VERSION 5.8 ;
BUSBITCHARS "[]" ;
DIVIDERCHAR "/" ;
UNITS
    DATABASE MICRONS 2000 ;
END UNITS

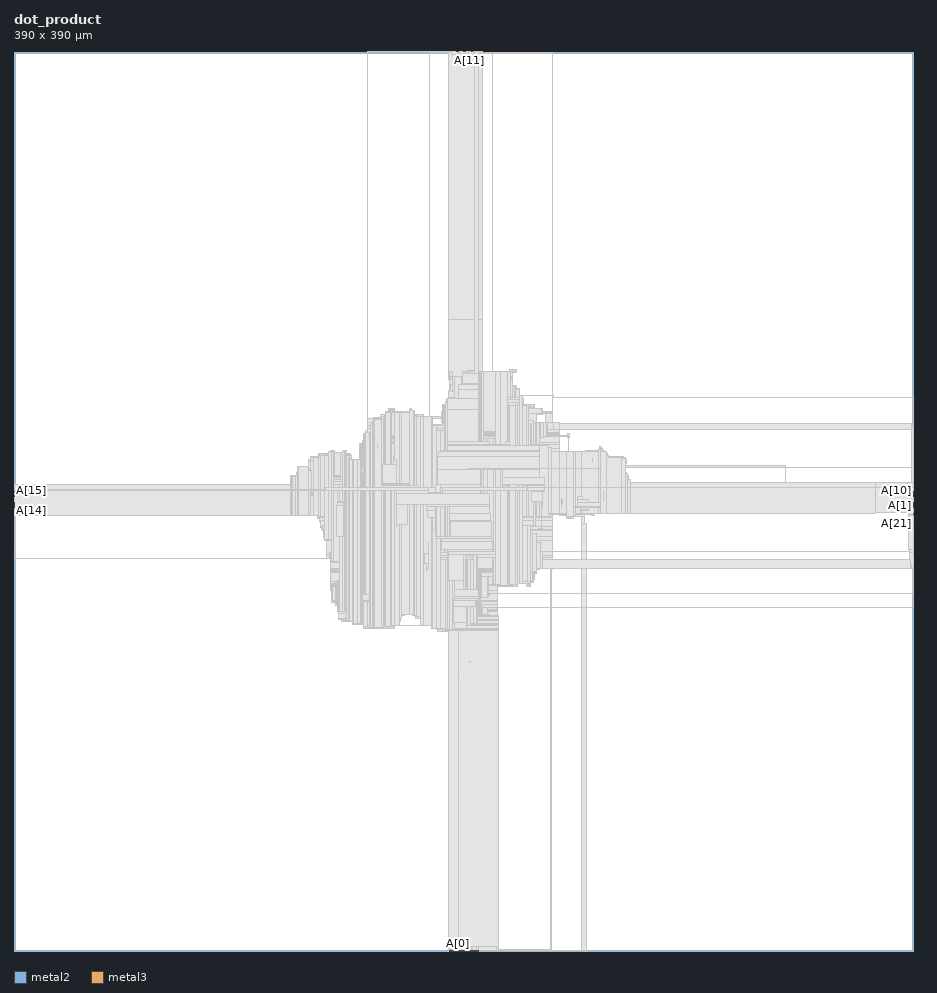
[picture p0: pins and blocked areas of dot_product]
MACRO dot_product
  FOREIGN dot_product 0 0 ;
  CLASS BLOCK ;
  SIZE 390 BY 390 ;
  PIN A[0]
    DIRECTION INPUT ;
    USE SIGNAL ;
    PORT
      LAYER metal2 ;
        RECT  192.34 0 192.41 0.07 ;
    END
  END A[0]
  PIN A[10]
    DIRECTION INPUT ;
    USE SIGNAL ;
    PORT
      LAYER metal3 ;
        RECT  389.93 199.675 390 199.745 ;
    END
  END A[10]
  PIN A[11]
    DIRECTION INPUT ;
    USE SIGNAL ;
    PORT
      LAYER metal2 ;
        RECT  197.28 389.93 197.35 390 ;
    END
  END A[11]
  PIN A[12]
    DIRECTION INPUT ;
    USE SIGNAL ;
    PORT
      LAYER metal3 ;
        RECT  389.93 194.915 390 194.985 ;
    END
  END A[12]
  PIN A[13]
    DIRECTION INPUT ;
    USE SIGNAL ;
    PORT
      LAYER metal2 ;
        RECT  196.52 0 196.59 0.07 ;
    END
  END A[13]
  PIN A[14]
    DIRECTION INPUT ;
    USE SIGNAL ;
    PORT
      LAYER metal3 ;
        RECT  0 190.715 0.07 190.785 ;
    END
  END A[14]
  PIN A[15]
    DIRECTION INPUT ;
    USE SIGNAL ;
    PORT
      LAYER metal3 ;
        RECT  0 196.035 0.07 196.105 ;
    END
  END A[15]
  PIN A[16]
    DIRECTION INPUT ;
    USE SIGNAL ;
    PORT
      LAYER metal3 ;
        RECT  0 198.835 0.07 198.905 ;
    END
  END A[16]
  PIN A[17]
    DIRECTION INPUT ;
    USE SIGNAL ;
    PORT
      LAYER metal3 ;
        RECT  389.93 194.355 390 194.425 ;
    END
  END A[17]
  PIN A[18]
    DIRECTION INPUT ;
    USE SIGNAL ;
    PORT
      LAYER metal3 ;
        RECT  0 197.155 0.07 197.225 ;
    END
  END A[18]
  PIN A[19]
    DIRECTION INPUT ;
    USE SIGNAL ;
    PORT
      LAYER metal3 ;
        RECT  0 196.315 0.07 196.385 ;
    END
  END A[19]
  PIN A[1]
    DIRECTION INPUT ;
    USE SIGNAL ;
    PORT
      LAYER metal3 ;
        RECT  389.93 192.955 390 193.025 ;
    END
  END A[1]
  PIN A[20]
    DIRECTION INPUT ;
    USE SIGNAL ;
    PORT
      LAYER metal2 ;
        RECT  196.9 0 196.97 0.07 ;
    END
  END A[20]
  PIN A[21]
    DIRECTION INPUT ;
    USE SIGNAL ;
    PORT
      LAYER metal3 ;
        RECT  389.93 188.755 390 188.825 ;
    END
  END A[21]
  PIN A[22]
    DIRECTION INPUT ;
    USE SIGNAL ;
    PORT
      LAYER metal2 ;
        RECT  188.92 0 188.99 0.07 ;
    END
  END A[22]
  PIN A[23]
    DIRECTION INPUT ;
    USE SIGNAL ;
    PORT
      LAYER metal2 ;
        RECT  190.44 389.93 190.51 390 ;
    END
  END A[23]
  PIN A[24]
    DIRECTION INPUT ;
    USE SIGNAL ;
    PORT
      LAYER metal2 ;
        RECT  192.34 389.93 192.41 390 ;
    END
  END A[24]
  PIN A[25]
    DIRECTION INPUT ;
    USE SIGNAL ;
    PORT
      LAYER metal3 ;
        RECT  0 194.635 0.07 194.705 ;
    END
  END A[25]
  PIN A[26]
    DIRECTION INPUT ;
    USE SIGNAL ;
    PORT
      LAYER metal3 ;
        RECT  0 194.075 0.07 194.145 ;
    END
  END A[26]
  PIN A[27]
    DIRECTION INPUT ;
    USE SIGNAL ;
    PORT
      LAYER metal3 ;
        RECT  0 199.955 0.07 200.025 ;
    END
  END A[27]
  PIN A[28]
    DIRECTION INPUT ;
    USE SIGNAL ;
    PORT
      LAYER metal3 ;
        RECT  0 189.315 0.07 189.385 ;
    END
  END A[28]
  PIN A[29]
    DIRECTION INPUT ;
    USE SIGNAL ;
    PORT
      LAYER metal2 ;
        RECT  194.62 389.93 194.69 390 ;
    END
  END A[29]
  PIN A[2]
    DIRECTION INPUT ;
    USE SIGNAL ;
    PORT
      LAYER metal2 ;
        RECT  200.7 389.93 200.77 390 ;
    END
  END A[2]
  PIN A[30]
    DIRECTION INPUT ;
    USE SIGNAL ;
    PORT
      LAYER metal2 ;
        RECT  199.56 389.93 199.63 390 ;
    END
  END A[30]
  PIN A[31]
    DIRECTION INPUT ;
    USE SIGNAL ;
    PORT
      LAYER metal3 ;
        RECT  0 196.595 0.07 196.665 ;
    END
  END A[31]
  PIN A[32]
    DIRECTION INPUT ;
    USE SIGNAL ;
    PORT
      LAYER metal2 ;
        RECT  193.86 389.93 193.93 390 ;
    END
  END A[32]
  PIN A[33]
    DIRECTION INPUT ;
    USE SIGNAL ;
    PORT
      LAYER metal3 ;
        RECT  0 197.715 0.07 197.785 ;
    END
  END A[33]
  PIN A[34]
    DIRECTION INPUT ;
    USE SIGNAL ;
    PORT
      LAYER metal2 ;
        RECT  193.48 0 193.55 0.07 ;
    END
  END A[34]
  PIN A[35]
    DIRECTION INPUT ;
    USE SIGNAL ;
    PORT
      LAYER metal3 ;
        RECT  0 191.835 0.07 191.905 ;
    END
  END A[35]
  PIN A[36]
    DIRECTION INPUT ;
    USE SIGNAL ;
    PORT
      LAYER metal3 ;
        RECT  0 200.235 0.07 200.305 ;
    END
  END A[36]
  PIN A[37]
    DIRECTION INPUT ;
    USE SIGNAL ;
    PORT
      LAYER metal3 ;
        RECT  0 192.675 0.07 192.745 ;
    END
  END A[37]
  PIN A[38]
    DIRECTION INPUT ;
    USE SIGNAL ;
    PORT
      LAYER metal3 ;
        RECT  389.93 201.355 390 201.425 ;
    END
  END A[38]
  PIN A[39]
    DIRECTION INPUT ;
    USE SIGNAL ;
    PORT
      LAYER metal3 ;
        RECT  389.93 196.595 390 196.665 ;
    END
  END A[39]
  PIN A[3]
    DIRECTION INPUT ;
    USE SIGNAL ;
    PORT
      LAYER metal3 ;
        RECT  389.93 196.875 390 196.945 ;
    END
  END A[3]
  PIN A[40]
    DIRECTION INPUT ;
    USE SIGNAL ;
    PORT
      LAYER metal2 ;
        RECT  191.96 389.93 192.03 390 ;
    END
  END A[40]
  PIN A[41]
    DIRECTION INPUT ;
    USE SIGNAL ;
    PORT
      LAYER metal2 ;
        RECT  190.82 0 190.89 0.07 ;
    END
  END A[41]
  PIN A[42]
    DIRECTION INPUT ;
    USE SIGNAL ;
    PORT
      LAYER metal2 ;
        RECT  197.28 0 197.35 0.07 ;
    END
  END A[42]
  PIN A[43]
    DIRECTION INPUT ;
    USE SIGNAL ;
    PORT
      LAYER metal3 ;
        RECT  389.93 197.435 390 197.505 ;
    END
  END A[43]
  PIN A[44]
    DIRECTION INPUT ;
    USE SIGNAL ;
    PORT
      LAYER metal3 ;
        RECT  389.93 189.875 390 189.945 ;
    END
  END A[44]
  PIN A[45]
    DIRECTION INPUT ;
    USE SIGNAL ;
    PORT
      LAYER metal3 ;
        RECT  0 195.195 0.07 195.265 ;
    END
  END A[45]
  PIN A[46]
    DIRECTION INPUT ;
    USE SIGNAL ;
    PORT
      LAYER metal3 ;
        RECT  0 194.355 0.07 194.425 ;
    END
  END A[46]
  PIN A[47]
    DIRECTION INPUT ;
    USE SIGNAL ;
    PORT
      LAYER metal3 ;
        RECT  389.93 198.835 390 198.905 ;
    END
  END A[47]
  PIN A[48]
    DIRECTION INPUT ;
    USE SIGNAL ;
    PORT
      LAYER metal2 ;
        RECT  199.94 389.93 200.01 390 ;
    END
  END A[48]
  PIN A[49]
    DIRECTION INPUT ;
    USE SIGNAL ;
    PORT
      LAYER metal2 ;
        RECT  200.32 0 200.39 0.07 ;
    END
  END A[49]
  PIN A[4]
    DIRECTION INPUT ;
    USE SIGNAL ;
    PORT
      LAYER metal2 ;
        RECT  190.06 389.93 190.13 390 ;
    END
  END A[4]
  PIN A[50]
    DIRECTION INPUT ;
    USE SIGNAL ;
    PORT
      LAYER metal3 ;
        RECT  0 192.115 0.07 192.185 ;
    END
  END A[50]
  PIN A[51]
    DIRECTION INPUT ;
    USE SIGNAL ;
    PORT
      LAYER metal3 ;
        RECT  389.93 191.835 390 191.905 ;
    END
  END A[51]
  PIN A[52]
    DIRECTION INPUT ;
    USE SIGNAL ;
    PORT
      LAYER metal3 ;
        RECT  389.93 199.395 390 199.465 ;
    END
  END A[52]
  PIN A[53]
    DIRECTION INPUT ;
    USE SIGNAL ;
    PORT
      LAYER metal2 ;
        RECT  196.9 389.93 196.97 390 ;
    END
  END A[53]
  PIN A[54]
    DIRECTION INPUT ;
    USE SIGNAL ;
    PORT
      LAYER metal2 ;
        RECT  189.68 389.93 189.75 390 ;
    END
  END A[54]
  PIN A[55]
    DIRECTION INPUT ;
    USE SIGNAL ;
    PORT
      LAYER metal3 ;
        RECT  389.93 193.515 390 193.585 ;
    END
  END A[55]
  PIN A[56]
    DIRECTION INPUT ;
    USE SIGNAL ;
    PORT
      LAYER metal2 ;
        RECT  190.06 0 190.13 0.07 ;
    END
  END A[56]
  PIN A[57]
    DIRECTION INPUT ;
    USE SIGNAL ;
    PORT
      LAYER metal2 ;
        RECT  195.38 0 195.45 0.07 ;
    END
  END A[57]
  PIN A[58]
    DIRECTION INPUT ;
    USE SIGNAL ;
    PORT
      LAYER metal3 ;
        RECT  0 198.275 0.07 198.345 ;
    END
  END A[58]
  PIN A[59]
    DIRECTION INPUT ;
    USE SIGNAL ;
    PORT
      LAYER metal3 ;
        RECT  389.93 190.435 390 190.505 ;
    END
  END A[59]
  PIN A[5]
    DIRECTION INPUT ;
    USE SIGNAL ;
    PORT
      LAYER metal3 ;
        RECT  0 198.555 0.07 198.625 ;
    END
  END A[5]
  PIN A[60]
    DIRECTION INPUT ;
    USE SIGNAL ;
    PORT
      LAYER metal3 ;
        RECT  0 190.435 0.07 190.505 ;
    END
  END A[60]
  PIN A[61]
    DIRECTION INPUT ;
    USE SIGNAL ;
    PORT
      LAYER metal2 ;
        RECT  198.8 0 198.87 0.07 ;
    END
  END A[61]
  PIN A[62]
    DIRECTION INPUT ;
    USE SIGNAL ;
    PORT
      LAYER metal3 ;
        RECT  389.93 198.555 390 198.625 ;
    END
  END A[62]
  PIN A[63]
    DIRECTION INPUT ;
    USE SIGNAL ;
    PORT
      LAYER metal2 ;
        RECT  195.76 0 195.83 0.07 ;
    END
  END A[63]
  PIN A[6]
    DIRECTION INPUT ;
    USE SIGNAL ;
    PORT
      LAYER metal2 ;
        RECT  195 0 195.07 0.07 ;
    END
  END A[6]
  PIN A[7]
    DIRECTION INPUT ;
    USE SIGNAL ;
    PORT
      LAYER metal2 ;
        RECT  198.8 389.93 198.87 390 ;
    END
  END A[7]
  PIN A[8]
    DIRECTION INPUT ;
    USE SIGNAL ;
    PORT
      LAYER metal3 ;
        RECT  0 193.795 0.07 193.865 ;
    END
  END A[8]
  PIN A[9]
    DIRECTION INPUT ;
    USE SIGNAL ;
    PORT
      LAYER metal2 ;
        RECT  192.72 389.93 192.79 390 ;
    END
  END A[9]
  PIN B[0]
    DIRECTION INPUT ;
    USE SIGNAL ;
    PORT
      LAYER metal3 ;
        RECT  0 195.755 0.07 195.825 ;
    END
  END B[0]
  PIN B[10]
    DIRECTION INPUT ;
    USE SIGNAL ;
    PORT
      LAYER metal3 ;
        RECT  389.93 199.115 390 199.185 ;
    END
  END B[10]
  PIN B[11]
    DIRECTION INPUT ;
    USE SIGNAL ;
    PORT
      LAYER metal3 ;
        RECT  0 201.075 0.07 201.145 ;
    END
  END B[11]
  PIN B[12]
    DIRECTION INPUT ;
    USE SIGNAL ;
    PORT
      LAYER metal2 ;
        RECT  194.24 0 194.31 0.07 ;
    END
  END B[12]
  PIN B[13]
    DIRECTION INPUT ;
    USE SIGNAL ;
    PORT
      LAYER metal2 ;
        RECT  193.86 0 193.93 0.07 ;
    END
  END B[13]
  PIN B[14]
    DIRECTION INPUT ;
    USE SIGNAL ;
    PORT
      LAYER metal3 ;
        RECT  0 193.515 0.07 193.585 ;
    END
  END B[14]
  PIN B[15]
    DIRECTION INPUT ;
    USE SIGNAL ;
    PORT
      LAYER metal3 ;
        RECT  0 199.675 0.07 199.745 ;
    END
  END B[15]
  PIN B[16]
    DIRECTION INPUT ;
    USE SIGNAL ;
    PORT
      LAYER metal3 ;
        RECT  0 195.475 0.07 195.545 ;
    END
  END B[16]
  PIN B[17]
    DIRECTION INPUT ;
    USE SIGNAL ;
    PORT
      LAYER metal2 ;
        RECT  196.14 0 196.21 0.07 ;
    END
  END B[17]
  PIN B[18]
    DIRECTION INPUT ;
    USE SIGNAL ;
    PORT
      LAYER metal3 ;
        RECT  0 194.915 0.07 194.985 ;
    END
  END B[18]
  PIN B[19]
    DIRECTION INPUT ;
    USE SIGNAL ;
    PORT
      LAYER metal3 ;
        RECT  0 190.995 0.07 191.065 ;
    END
  END B[19]
  PIN B[1]
    DIRECTION INPUT ;
    USE SIGNAL ;
    PORT
      LAYER metal2 ;
        RECT  191.2 0 191.27 0.07 ;
    END
  END B[1]
  PIN B[20]
    DIRECTION INPUT ;
    USE SIGNAL ;
    PORT
      LAYER metal3 ;
        RECT  0 199.115 0.07 199.185 ;
    END
  END B[20]
  PIN B[21]
    DIRECTION INPUT ;
    USE SIGNAL ;
    PORT
      LAYER metal2 ;
        RECT  194.62 0 194.69 0.07 ;
    END
  END B[21]
  PIN B[22]
    DIRECTION INPUT ;
    USE SIGNAL ;
    PORT
      LAYER metal3 ;
        RECT  389.93 189.595 390 189.665 ;
    END
  END B[22]
  PIN B[23]
    DIRECTION INPUT ;
    USE SIGNAL ;
    PORT
      LAYER metal2 ;
        RECT  193.1 0 193.17 0.07 ;
    END
  END B[23]
  PIN B[24]
    DIRECTION INPUT ;
    USE SIGNAL ;
    PORT
      LAYER metal2 ;
        RECT  190.82 389.93 190.89 390 ;
    END
  END B[24]
  PIN B[25]
    DIRECTION INPUT ;
    USE SIGNAL ;
    PORT
      LAYER metal3 ;
        RECT  389.93 194.635 390 194.705 ;
    END
  END B[25]
  PIN B[26]
    DIRECTION INPUT ;
    USE SIGNAL ;
    PORT
      LAYER metal2 ;
        RECT  195 389.93 195.07 390 ;
    END
  END B[26]
  PIN B[27]
    DIRECTION INPUT ;
    USE SIGNAL ;
    PORT
      LAYER metal2 ;
        RECT  192.72 0 192.79 0.07 ;
    END
  END B[27]
  PIN B[28]
    DIRECTION INPUT ;
    USE SIGNAL ;
    PORT
      LAYER metal3 ;
        RECT  0 190.155 0.07 190.225 ;
    END
  END B[28]
  PIN B[29]
    DIRECTION INPUT ;
    USE SIGNAL ;
    PORT
      LAYER metal3 ;
        RECT  389.93 200.235 390 200.305 ;
    END
  END B[29]
  PIN B[2]
    DIRECTION INPUT ;
    USE SIGNAL ;
    PORT
      LAYER metal2 ;
        RECT  198.04 0 198.11 0.07 ;
    END
  END B[2]
  PIN B[30]
    DIRECTION INPUT ;
    USE SIGNAL ;
    PORT
      LAYER metal3 ;
        RECT  389.93 191.275 390 191.345 ;
    END
  END B[30]
  PIN B[31]
    DIRECTION INPUT ;
    USE SIGNAL ;
    PORT
      LAYER metal3 ;
        RECT  0 200.515 0.07 200.585 ;
    END
  END B[31]
  PIN B[32]
    DIRECTION INPUT ;
    USE SIGNAL ;
    PORT
      LAYER metal2 ;
        RECT  201.08 0 201.15 0.07 ;
    END
  END B[32]
  PIN B[33]
    DIRECTION INPUT ;
    USE SIGNAL ;
    PORT
      LAYER metal3 ;
        RECT  0 201.635 0.07 201.705 ;
    END
  END B[33]
  PIN B[34]
    DIRECTION INPUT ;
    USE SIGNAL ;
    PORT
      LAYER metal2 ;
        RECT  193.48 389.93 193.55 390 ;
    END
  END B[34]
  PIN B[35]
    DIRECTION INPUT ;
    USE SIGNAL ;
    PORT
      LAYER metal2 ;
        RECT  195.38 389.93 195.45 390 ;
    END
  END B[35]
  PIN B[36]
    DIRECTION INPUT ;
    USE SIGNAL ;
    PORT
      LAYER metal3 ;
        RECT  389.93 197.155 390 197.225 ;
    END
  END B[36]
  PIN B[37]
    DIRECTION INPUT ;
    USE SIGNAL ;
    PORT
      LAYER metal2 ;
        RECT  189.68 0 189.75 0.07 ;
    END
  END B[37]
  PIN B[38]
    DIRECTION INPUT ;
    USE SIGNAL ;
    PORT
      LAYER metal3 ;
        RECT  0 197.995 0.07 198.065 ;
    END
  END B[38]
  PIN B[39]
    DIRECTION INPUT ;
    USE SIGNAL ;
    PORT
      LAYER metal3 ;
        RECT  389.93 192.675 390 192.745 ;
    END
  END B[39]
  PIN B[3]
    DIRECTION INPUT ;
    USE SIGNAL ;
    PORT
      LAYER metal3 ;
        RECT  0 192.955 0.07 193.025 ;
    END
  END B[3]
  PIN B[40]
    DIRECTION INPUT ;
    USE SIGNAL ;
    PORT
      LAYER metal2 ;
        RECT  191.96 0 192.03 0.07 ;
    END
  END B[40]
  PIN B[41]
    DIRECTION INPUT ;
    USE SIGNAL ;
    PORT
      LAYER metal3 ;
        RECT  389.93 197.995 390 198.065 ;
    END
  END B[41]
  PIN B[42]
    DIRECTION INPUT ;
    USE SIGNAL ;
    PORT
      LAYER metal3 ;
        RECT  389.93 189.315 390 189.385 ;
    END
  END B[42]
  PIN B[43]
    DIRECTION INPUT ;
    USE SIGNAL ;
    PORT
      LAYER metal3 ;
        RECT  389.93 197.715 390 197.785 ;
    END
  END B[43]
  PIN B[44]
    DIRECTION INPUT ;
    USE SIGNAL ;
    PORT
      LAYER metal3 ;
        RECT  389.93 195.475 390 195.545 ;
    END
  END B[44]
  PIN B[45]
    DIRECTION INPUT ;
    USE SIGNAL ;
    PORT
      LAYER metal3 ;
        RECT  389.93 190.155 390 190.225 ;
    END
  END B[45]
  PIN B[46]
    DIRECTION INPUT ;
    USE SIGNAL ;
    PORT
      LAYER metal2 ;
        RECT  198.42 0 198.49 0.07 ;
    END
  END B[46]
  PIN B[47]
    DIRECTION INPUT ;
    USE SIGNAL ;
    PORT
      LAYER metal3 ;
        RECT  389.93 199.955 390 200.025 ;
    END
  END B[47]
  PIN B[48]
    DIRECTION INPUT ;
    USE SIGNAL ;
    PORT
      LAYER metal2 ;
        RECT  201.84 389.93 201.91 390 ;
    END
  END B[48]
  PIN B[49]
    DIRECTION INPUT ;
    USE SIGNAL ;
    PORT
      LAYER metal2 ;
        RECT  196.14 389.93 196.21 390 ;
    END
  END B[49]
  PIN B[4]
    DIRECTION INPUT ;
    USE SIGNAL ;
    PORT
      LAYER metal2 ;
        RECT  197.66 0 197.73 0.07 ;
    END
  END B[4]
  PIN B[50]
    DIRECTION INPUT ;
    USE SIGNAL ;
    PORT
      LAYER metal2 ;
        RECT  191.58 0 191.65 0.07 ;
    END
  END B[50]
  PIN B[51]
    DIRECTION INPUT ;
    USE SIGNAL ;
    PORT
      LAYER metal2 ;
        RECT  198.04 389.93 198.11 390 ;
    END
  END B[51]
  PIN B[52]
    DIRECTION INPUT ;
    USE SIGNAL ;
    PORT
      LAYER metal2 ;
        RECT  190.44 0 190.51 0.07 ;
    END
  END B[52]
  PIN B[53]
    DIRECTION INPUT ;
    USE SIGNAL ;
    PORT
      LAYER metal3 ;
        RECT  389.93 196.315 390 196.385 ;
    END
  END B[53]
  PIN B[54]
    DIRECTION INPUT ;
    USE SIGNAL ;
    PORT
      LAYER metal3 ;
        RECT  0 192.395 0.07 192.465 ;
    END
  END B[54]
  PIN B[55]
    DIRECTION INPUT ;
    USE SIGNAL ;
    PORT
      LAYER metal3 ;
        RECT  0 191.275 0.07 191.345 ;
    END
  END B[55]
  PIN B[56]
    DIRECTION INPUT ;
    USE SIGNAL ;
    PORT
      LAYER metal3 ;
        RECT  389.93 193.235 390 193.305 ;
    END
  END B[56]
  PIN B[57]
    DIRECTION INPUT ;
    USE SIGNAL ;
    PORT
      LAYER metal2 ;
        RECT  199.56 0 199.63 0.07 ;
    END
  END B[57]
  PIN B[58]
    DIRECTION INPUT ;
    USE SIGNAL ;
    PORT
      LAYER metal3 ;
        RECT  0 189.875 0.07 189.945 ;
    END
  END B[58]
  PIN B[59]
    DIRECTION INPUT ;
    USE SIGNAL ;
    PORT
      LAYER metal2 ;
        RECT  197.66 389.93 197.73 390 ;
    END
  END B[59]
  PIN B[5]
    DIRECTION INPUT ;
    USE SIGNAL ;
    PORT
      LAYER metal3 ;
        RECT  0 189.035 0.07 189.105 ;
    END
  END B[5]
  PIN B[60]
    DIRECTION INPUT ;
    USE SIGNAL ;
    PORT
      LAYER metal2 ;
        RECT  199.94 0 200.01 0.07 ;
    END
  END B[60]
  PIN B[61]
    DIRECTION INPUT ;
    USE SIGNAL ;
    PORT
      LAYER metal3 ;
        RECT  389.93 196.035 390 196.105 ;
    END
  END B[61]
  PIN B[62]
    DIRECTION INPUT ;
    USE SIGNAL ;
    PORT
      LAYER metal2 ;
        RECT  199.18 389.93 199.25 390 ;
    END
  END B[62]
  PIN B[63]
    DIRECTION INPUT ;
    USE SIGNAL ;
    PORT
      LAYER metal3 ;
        RECT  389.93 192.395 390 192.465 ;
    END
  END B[63]
  PIN B[6]
    DIRECTION INPUT ;
    USE SIGNAL ;
    PORT
      LAYER metal2 ;
        RECT  189.3 0 189.37 0.07 ;
    END
  END B[6]
  PIN B[7]
    DIRECTION INPUT ;
    USE SIGNAL ;
    PORT
      LAYER metal2 ;
        RECT  198.42 389.93 198.49 390 ;
    END
  END B[7]
  PIN B[8]
    DIRECTION INPUT ;
    USE SIGNAL ;
    PORT
      LAYER metal2 ;
        RECT  200.7 0 200.77 0.07 ;
    END
  END B[8]
  PIN B[9]
    DIRECTION INPUT ;
    USE SIGNAL ;
    PORT
      LAYER metal3 ;
        RECT  389.93 190.715 390 190.785 ;
    END
  END B[9]
  PIN clk
    DIRECTION INPUT ;
    USE SIGNAL ;
    PORT
      LAYER metal3 ;
        RECT  389.93 193.795 390 193.865 ;
    END
  END clk
  PIN dot_out[0]
    DIRECTION OUTPUT ;
    USE SIGNAL ;
    PORT
      LAYER metal2 ;
        RECT  196.52 389.93 196.59 390 ;
    END
  END dot_out[0]
  PIN dot_out[10]
    DIRECTION OUTPUT ;
    USE SIGNAL ;
    PORT
      LAYER metal2 ;
        RECT  191.2 389.93 191.27 390 ;
    END
  END dot_out[10]
  PIN dot_out[11]
    DIRECTION OUTPUT ;
    USE SIGNAL ;
    PORT
      LAYER metal3 ;
        RECT  0 193.235 0.07 193.305 ;
    END
  END dot_out[11]
  PIN dot_out[12]
    DIRECTION OUTPUT ;
    USE SIGNAL ;
    PORT
      LAYER metal2 ;
        RECT  193.1 389.93 193.17 390 ;
    END
  END dot_out[12]
  PIN dot_out[13]
    DIRECTION OUTPUT ;
    USE SIGNAL ;
    PORT
      LAYER metal3 ;
        RECT  0 197.435 0.07 197.505 ;
    END
  END dot_out[13]
  PIN dot_out[14]
    DIRECTION OUTPUT ;
    USE SIGNAL ;
    PORT
      LAYER metal2 ;
        RECT  194.24 389.93 194.31 390 ;
    END
  END dot_out[14]
  PIN dot_out[15]
    DIRECTION OUTPUT ;
    USE SIGNAL ;
    PORT
      LAYER metal3 ;
        RECT  389.93 190.995 390 191.065 ;
    END
  END dot_out[15]
  PIN dot_out[16]
    DIRECTION OUTPUT ;
    USE SIGNAL ;
    PORT
      LAYER metal3 ;
        RECT  0 200.795 0.07 200.865 ;
    END
  END dot_out[16]
  PIN dot_out[17]
    DIRECTION OUTPUT ;
    USE SIGNAL ;
    PORT
      LAYER metal3 ;
        RECT  0 199.395 0.07 199.465 ;
    END
  END dot_out[17]
  PIN dot_out[18]
    DIRECTION OUTPUT ;
    USE SIGNAL ;
    PORT
      LAYER metal3 ;
        RECT  0 189.595 0.07 189.665 ;
    END
  END dot_out[18]
  PIN dot_out[19]
    DIRECTION OUTPUT ;
    USE SIGNAL ;
    PORT
      LAYER metal3 ;
        RECT  0 196.875 0.07 196.945 ;
    END
  END dot_out[19]
  PIN dot_out[1]
    DIRECTION OUTPUT ;
    USE SIGNAL ;
    PORT
      LAYER metal2 ;
        RECT  195.76 389.93 195.83 390 ;
    END
  END dot_out[1]
  PIN dot_out[2]
    DIRECTION OUTPUT ;
    USE SIGNAL ;
    PORT
      LAYER metal3 ;
        RECT  389.93 198.275 390 198.345 ;
    END
  END dot_out[2]
  PIN dot_out[3]
    DIRECTION OUTPUT ;
    USE SIGNAL ;
    PORT
      LAYER metal3 ;
        RECT  389.93 194.075 390 194.145 ;
    END
  END dot_out[3]
  PIN dot_out[4]
    DIRECTION OUTPUT ;
    USE SIGNAL ;
    PORT
      LAYER metal3 ;
        RECT  389.93 191.555 390 191.625 ;
    END
  END dot_out[4]
  PIN dot_out[5]
    DIRECTION OUTPUT ;
    USE SIGNAL ;
    PORT
      LAYER metal3 ;
        RECT  389.93 195.755 390 195.825 ;
    END
  END dot_out[5]
  PIN dot_out[6]
    DIRECTION OUTPUT ;
    USE SIGNAL ;
    PORT
      LAYER metal3 ;
        RECT  0 191.555 0.07 191.625 ;
    END
  END dot_out[6]
  PIN dot_out[7]
    DIRECTION OUTPUT ;
    USE SIGNAL ;
    PORT
      LAYER metal2 ;
        RECT  188.16 389.93 188.23 390 ;
    END
  END dot_out[7]
  PIN dot_out[8]
    DIRECTION OUTPUT ;
    USE SIGNAL ;
    PORT
      LAYER metal2 ;
        RECT  191.58 389.93 191.65 390 ;
    END
  END dot_out[8]
  PIN dot_out[9]
    DIRECTION OUTPUT ;
    USE SIGNAL ;
    PORT
      LAYER metal3 ;
        RECT  389.93 192.115 390 192.185 ;
    END
  END dot_out[9]
  PIN rst
    DIRECTION INPUT ;
    USE SIGNAL ;
    PORT
      LAYER metal3 ;
        RECT  389.93 195.195 390 195.265 ;
    END
  END rst
  PIN valid
    DIRECTION OUTPUT ;
    USE SIGNAL ;
    PORT
      LAYER metal2 ;
        RECT  199.18 0 199.25 0.07 ;
    END
  END valid
  OBS
    LAYER metal1 ;
     RECT  120.08 195.915 120.46 197.485 ;
     RECT  119.89 204.315 120.46 205.885 ;
     RECT  120.46 195.915 121.41 205.885 ;
     RECT  121.41 194.515 122.36 205.885 ;
     RECT  122.36 194.515 122.55 207.285 ;
     RECT  122.55 190.315 122.74 207.285 ;
     RECT  122.74 190.315 123.5 210.085 ;
     RECT  123.5 188.915 127.49 210.085 ;
     RECT  127.49 188.915 128.63 212.885 ;
     RECT  128.63 188.915 131.67 214.285 ;
     RECT  131.67 187.515 132.05 214.285 ;
     RECT  132.05 187.515 132.24 215.685 ;
     RECT  132.24 186.115 132.81 215.685 ;
     RECT  132.81 183.315 134.14 215.685 ;
     RECT  134.14 181.915 134.33 215.685 ;
     RECT  134.33 179.115 134.52 215.685 ;
     RECT  134.52 177.715 137.18 215.685 ;
     RECT  137.18 156.715 137.37 158.285 ;
     RECT  137.37 155.315 137.75 158.285 ;
     RECT  137.18 177.715 137.75 217.085 ;
     RECT  137.75 176.315 137.94 217.085 ;
     RECT  137.94 174.915 138.32 217.085 ;
     RECT  138.32 173.515 138.51 217.085 ;
     RECT  138.51 172.115 138.7 217.085 ;
     RECT  138.7 172.115 138.89 215.685 ;
     RECT  137.75 151.115 139.27 158.285 ;
     RECT  139.27 149.715 140.22 161.085 ;
     RECT  138.89 170.715 140.79 215.685 ;
     RECT  140.22 146.915 141.93 165.285 ;
     RECT  140.79 169.315 141.93 215.685 ;
     RECT  141.93 142.715 142.88 215.685 ;
     RECT  142.88 142.715 144.02 217.085 ;
     RECT  144.02 142.715 145.92 215.685 ;
     RECT  145.92 142.715 146.87 212.885 ;
     RECT  146.87 141.315 149.91 212.885 ;
     RECT  149.53 218.315 149.91 219.885 ;
     RECT  149.91 141.315 151.05 219.885 ;
     RECT  151.05 141.315 151.24 221.285 ;
     RECT  151.24 139.915 151.43 221.285 ;
     RECT  151.43 139.915 152.38 224.085 ;
     RECT  152.38 139.915 154.47 225.485 ;
     RECT  154.47 139.915 155.8 229.685 ;
     RECT  155.8 139.915 158.65 231.085 ;
     RECT  158.65 139.915 160.93 232.485 ;
     RECT  160.93 139.915 162.26 233.885 ;
     RECT  162.26 139.915 164.73 235.285 ;
     RECT  164.73 139.915 164.92 233.885 ;
     RECT  164.92 141.315 166.06 233.885 ;
     RECT  166.06 142.715 167.39 233.885 ;
     RECT  167.39 145.515 169.29 233.885 ;
     RECT  169.29 146.915 171.76 233.885 ;
     RECT  171.76 146.915 172.33 235.285 ;
     RECT  172.33 146.915 172.52 233.885 ;
     RECT  172.52 145.515 173.47 233.885 ;
     RECT  173.47 145.515 173.85 232.485 ;
     RECT  173.85 144.115 176.51 232.485 ;
     RECT  176.51 142.715 177.46 232.485 ;
     RECT  177.46 142.715 177.84 231.085 ;
     RECT  177.84 141.315 179.36 231.085 ;
     RECT  179.36 141.315 181.45 229.685 ;
     RECT  181.45 141.315 182.4 228.285 ;
     RECT  182.4 139.915 183.54 228.285 ;
     RECT  185.44 232.315 185.63 233.885 ;
     RECT  183.54 138.515 185.82 228.285 ;
     RECT  185.63 232.315 185.82 236.685 ;
     RECT  185.82 138.515 187.15 236.685 ;
     RECT  187.15 138.515 187.53 238.085 ;
     RECT  187.53 138.515 189.05 239.485 ;
     RECT  188.48 247.715 189.24 249.285 ;
     RECT  189.05 138.515 189.81 243.685 ;
     RECT  189.24 247.715 189.81 252.085 ;
     RECT  189.81 138.515 192.47 252.085 ;
     RECT  192.47 138.515 194.56 250.685 ;
     RECT  194.56 139.915 195.51 250.685 ;
     RECT  195.51 141.315 195.89 250.685 ;
     RECT  195.89 141.315 199.12 252.085 ;
     RECT  199.12 167.915 199.5 249.285 ;
     RECT  199.12 141.315 199.69 163.885 ;
     RECT  199.69 142.715 201.21 163.885 ;
     RECT  201.21 144.115 202.92 163.885 ;
     RECT  199.5 170.715 203.3 249.285 ;
     RECT  202.92 144.115 204.25 148.485 ;
     RECT  202.92 152.515 204.44 163.885 ;
     RECT  203.3 169.315 204.44 249.285 ;
     RECT  204.25 144.115 205.01 147.085 ;
     RECT  204.44 152.515 205.01 249.285 ;
     RECT  205.01 145.515 205.96 147.085 ;
     RECT  205.01 153.915 206.72 249.285 ;
     RECT  206.72 158.115 208.43 249.285 ;
     RECT  208.43 158.115 213.94 247.885 ;
     RECT  213.94 158.115 214.51 249.285 ;
     RECT  214.51 158.115 216.03 252.085 ;
     RECT  216.03 158.115 217.74 245.085 ;
     RECT  216.03 250.515 217.74 252.085 ;
     RECT  217.74 158.115 218.31 243.685 ;
     RECT  218.31 159.515 219.26 243.685 ;
     RECT  219.26 159.515 220.59 239.485 ;
     RECT  220.59 159.515 222.11 236.685 ;
     RECT  222.11 158.115 223.63 236.685 ;
     RECT  223.63 159.515 225.15 236.685 ;
     RECT  225.15 160.915 225.34 226.885 ;
     RECT  225.15 230.915 225.34 236.685 ;
     RECT  225.34 230.915 226.1 232.485 ;
     RECT  225.34 163.715 226.29 226.885 ;
     RECT  226.29 165.115 227.43 226.885 ;
     RECT  227.43 165.115 227.62 212.885 ;
     RECT  227.62 167.915 228 212.885 ;
     RECT  227.43 216.915 228.19 226.885 ;
     RECT  226.1 232.315 228.38 232.485 ;
     RECT  228 170.715 228.95 212.885 ;
     RECT  228.38 232.315 228.95 235.285 ;
     RECT  228.95 170.715 229.14 172.285 ;
     RECT  228.95 184.715 229.9 212.885 ;
     RECT  228.19 216.915 229.9 225.485 ;
     RECT  229.9 222.515 231.04 225.485 ;
     RECT  228.95 177.715 231.23 179.285 ;
     RECT  229.9 184.715 231.42 211.485 ;
     RECT  229.9 216.915 231.61 218.485 ;
     RECT  231.04 222.515 231.61 224.085 ;
     RECT  231.42 188.915 233.13 211.485 ;
     RECT  231.61 215.515 233.13 218.485 ;
     RECT  233.13 190.315 236.36 218.485 ;
     RECT  236.36 190.315 236.55 211.485 ;
     RECT  236.36 216.915 236.55 218.485 ;
     RECT  236.55 188.915 239.4 211.485 ;
     RECT  239.4 187.515 239.78 211.485 ;
     RECT  239.97 222.515 240.54 224.085 ;
     RECT  239.78 187.515 242.25 208.685 ;
     RECT  242.25 188.915 242.63 208.685 ;
     RECT  242.63 188.915 243.2 210.085 ;
     RECT  243.2 188.915 246.43 211.485 ;
     RECT  246.43 190.315 247.19 211.485 ;
     RECT  247.19 190.315 247.57 212.885 ;
     RECT  247.57 190.315 250.23 217.085 ;
     RECT  250.23 188.915 251.37 217.085 ;
     RECT  251.37 190.315 253.84 217.085 ;
     RECT  253.84 190.315 254.41 218.485 ;
     RECT  254.41 190.315 255.93 217.085 ;
     RECT  255.93 190.315 257.07 215.685 ;
     RECT  257.07 190.315 258.4 214.285 ;
     RECT  258.4 191.715 261.06 214.285 ;
     RECT  261.06 194.515 264.29 214.285 ;
     RECT  264.29 194.515 265.05 212.885 ;
     RECT  265.05 194.515 265.43 207.285 ;
     RECT  265.05 211.315 265.43 212.885 ;
     RECT  265.43 194.515 265.62 205.885 ;
     RECT  265.62 195.915 266.19 205.885 ;
     RECT  266.19 195.915 266.38 204.485 ;
     RECT  266.38 197.315 266.76 204.485 ;
     RECT  266.76 198.715 267.33 204.485 ;
     RECT  267.33 198.715 267.9 200.285 ;
     RECT  333.45 193.115 334.21 194.685 ;
     RECT  334.21 193.115 337.63 198.885 ;
     RECT  337.63 191.715 338.2 198.885 ;
     RECT  338.2 191.715 338.58 197.485 ;
     RECT  338.58 190.315 340.67 197.485 ;
     RECT  340.67 190.315 341.81 196.085 ;
     RECT  341.81 194.515 344.09 196.085 ;
    LAYER metal2 ;
     RECT  188.16 0 190.32 0.035 ;
     RECT  194.43 0 194.5 0.035 ;
     RECT  188.16 0.035 201.15 0.14 ;
     RECT  247.82 0 247.89 0.14 ;
     RECT  232.62 0.28 232.69 0.42 ;
     RECT  188.16 0.14 201.53 0.7 ;
     RECT  188.16 0.7 203.81 0.98 ;
     RECT  207.73 0.84 207.8 0.98 ;
     RECT  188.16 0.98 207.8 1.26 ;
     RECT  188.16 1.26 210.08 139.02 ;
     RECT  187.59 139.02 210.08 139.16 ;
     RECT  183.6 139.16 210.08 139.195 ;
     RECT  183.22 139.195 210.08 139.86 ;
     RECT  153.39 140 153.46 140.28 ;
     RECT  160.04 140 160.11 140.28 ;
     RECT  153.39 140.28 160.11 140.42 ;
     RECT  151.68 140.42 162.77 140.56 ;
     RECT  151.68 140.56 163.53 140.7 ;
     RECT  180.75 139.86 210.08 141.12 ;
     RECT  179.61 141.12 210.08 141.575 ;
     RECT  151.3 140.7 164.86 141.68 ;
     RECT  149.02 141.68 165.05 141.82 ;
     RECT  147.69 141.82 165.62 141.96 ;
     RECT  178.28 141.575 210.08 141.96 ;
     RECT  146.93 141.96 165.62 142.52 ;
     RECT  146.93 142.52 166 142.94 ;
     RECT  144.84 142.94 166 143.22 ;
     RECT  177.9 141.96 210.08 143.22 ;
     RECT  142.75 143.22 166 143.5 ;
     RECT  177.52 143.22 210.08 143.5 ;
     RECT  141.99 143.5 167.33 143.78 ;
     RECT  140.66 143.78 167.33 143.92 ;
     RECT  176 143.5 210.08 144.76 ;
     RECT  173.91 144.76 210.08 145.32 ;
     RECT  173.34 145.32 210.08 145.385 ;
     RECT  140.66 143.92 167.71 146.3 ;
     RECT  140.66 146.3 169.23 147.28 ;
     RECT  173.34 145.385 209.7 147.28 ;
     RECT  140.66 147.28 209.7 147.56 ;
     RECT  140.28 147.56 209.7 148.015 ;
     RECT  140.09 148.015 209.7 150.22 ;
     RECT  139.71 150.22 209.7 150.36 ;
     RECT  139.33 150.36 209.7 151.655 ;
     RECT  138.38 151.655 209.7 151.9 ;
     RECT  137.81 151.9 209.7 151.935 ;
     RECT  389.75 148.96 389.82 154.98 ;
     RECT  137.43 151.935 209.7 156.275 ;
     RECT  137.24 156.275 209.7 158.48 ;
     RECT  137.24 158.48 214.64 158.515 ;
     RECT  223.5 158.48 223.57 158.515 ;
     RECT  137.24 158.515 216.35 158.76 ;
     RECT  223.5 158.515 223.76 158.76 ;
     RECT  137.24 158.76 218.25 159.18 ;
     RECT  222.17 158.76 223.76 159.18 ;
     RECT  137.24 159.18 223.76 160.02 ;
     RECT  137.24 160.02 223.95 160.055 ;
     RECT  137.24 160.055 225.09 163.835 ;
     RECT  137.24 163.835 226.04 164.36 ;
     RECT  137.24 164.36 226.23 164.955 ;
     RECT  137.24 164.955 226.42 165.265 ;
     RECT  232.62 0.42 233.07 165.265 ;
     RECT  137.05 165.265 226.42 165.9 ;
     RECT  389.37 154.98 389.82 166.04 ;
     RECT  388.99 166.04 389.82 166.18 ;
     RECT  137.05 165.9 227.56 168.56 ;
     RECT  232.62 165.265 233.26 168.56 ;
     RECT  137.05 168.56 233.26 170.38 ;
     RECT  135.72 170.38 233.26 171.5 ;
     RECT  388.23 166.18 389.82 172.9 ;
     RECT  0.06 169.96 0.13 173.815 ;
     RECT  388.04 172.9 389.82 173.815 ;
     RECT  0.06 173.815 0.7 173.885 ;
     RECT  135.53 171.5 233.26 178.08 ;
     RECT  134.77 178.08 233.26 179.62 ;
     RECT  134.39 179.62 233.26 182.42 ;
     RECT  133.63 182.42 233.26 182.56 ;
     RECT  133.44 182.56 233.26 183.82 ;
     RECT  133.06 183.82 233.26 183.96 ;
     RECT  245.92 0.14 247.89 185.215 ;
     RECT  245.73 185.215 247.89 185.285 ;
     RECT  132.87 183.96 233.26 186.62 ;
     RECT  132.49 186.62 233.26 186.655 ;
     RECT  132.3 186.655 233.26 187.74 ;
     RECT  239.84 187.88 239.91 187.915 ;
     RECT  239.84 187.915 240.1 188.055 ;
     RECT  131.92 187.74 233.26 188.3 ;
     RECT  239.84 188.055 241.24 188.3 ;
     RECT  245.73 185.285 247.32 188.3 ;
     RECT  0.63 173.885 0.7 188.86 ;
     RECT  131.73 188.3 233.26 189.28 ;
     RECT  239.46 188.3 247.32 189.28 ;
     RECT  128.88 189.28 233.26 189.315 ;
     RECT  237.75 189.28 247.32 189.315 ;
     RECT  0.06 188.86 0.7 189.56 ;
     RECT  128.88 189.315 250.74 189.56 ;
     RECT  123.56 189.56 251.31 190.12 ;
     RECT  122.61 190.12 251.31 190.54 ;
     RECT  255.42 190.26 255.49 190.54 ;
     RECT  122.61 190.54 255.49 190.82 ;
     RECT  265.87 190.96 265.94 191.1 ;
     RECT  339.4 191.1 340.23 191.38 ;
     RECT  122.61 190.82 259.1 191.94 ;
     RECT  122.61 191.94 260.05 192.22 ;
     RECT  265.3 191.1 265.94 192.22 ;
     RECT  339.4 191.38 341.75 192.22 ;
     RECT  339.4 192.22 344.03 192.36 ;
     RECT  338.45 192.36 344.03 193.34 ;
     RECT  387.47 173.815 389.82 193.34 ;
     RECT  333.89 193.48 333.96 193.515 ;
     RECT  337.88 193.34 344.03 193.515 ;
     RECT  122.61 192.22 265.94 193.76 ;
     RECT  333.89 193.515 344.03 193.9 ;
     RECT  6.33 193.76 6.4 194.04 ;
     RECT  5.76 194.04 6.4 194.18 ;
     RECT  333.51 193.9 344.03 194.18 ;
     RECT  6.33 194.18 6.4 194.32 ;
     RECT  387.28 193.34 389.82 194.46 ;
     RECT  333.89 194.18 344.03 194.6 ;
     RECT  387.28 194.46 389.63 194.6 ;
     RECT  105.51 191.1 105.58 195.02 ;
     RECT  334.27 194.6 344.03 195.02 ;
     RECT  121.66 193.76 265.94 195.16 ;
     RECT  121.66 195.16 267.27 195.3 ;
     RECT  334.27 195.02 342.51 195.3 ;
     RECT  334.27 195.3 341.75 196.245 ;
     RECT  121.66 195.3 267.46 196.42 ;
     RECT  120.71 196.42 267.46 196.7 ;
     RECT  0.06 189.56 0.89 197.4 ;
     RECT  334.27 196.245 340.61 197.4 ;
     RECT  79.86 197.12 79.93 197.68 ;
     RECT  334.27 197.4 338.52 197.68 ;
     RECT  334.27 197.68 338.14 197.82 ;
     RECT  334.27 197.82 336.62 198.1 ;
     RECT  334.27 198.1 335.86 198.485 ;
     RECT  334.27 198.485 334.72 198.52 ;
     RECT  387.09 194.6 389.63 198.8 ;
     RECT  334.27 198.52 334.53 199.36 ;
     RECT  120.14 196.7 267.46 199.5 ;
     RECT  0.06 197.4 0.7 200.62 ;
     RECT  120.14 199.5 267.84 200.76 ;
     RECT  105.51 199.92 105.58 201.04 ;
     RECT  0.25 200.62 0.7 201.32 ;
     RECT  0.44 201.32 0.7 202.02 ;
     RECT  0.44 202.02 0.51 202.3 ;
     RECT  387.09 198.8 389.82 203 ;
     RECT  120.14 200.76 267.27 203.28 ;
     RECT  119.95 203.28 267.27 204.26 ;
     RECT  119.95 204.26 266.13 204.505 ;
     RECT  119.95 204.505 265.75 205.24 ;
     RECT  120.33 205.24 265.75 205.52 ;
     RECT  121.85 205.52 265.75 206.08 ;
     RECT  122.42 206.08 265.75 206.5 ;
     RECT  122.8 206.5 265.75 206.78 ;
     RECT  122.8 206.78 265.18 209.58 ;
     RECT  388.8 203 389.82 209.72 ;
     RECT  123.37 209.58 265.18 210 ;
     RECT  127.55 210 265.18 210.42 ;
     RECT  334.27 199.36 334.34 210.42 ;
     RECT  243.26 210.42 265.18 210.665 ;
     RECT  127.55 210.42 238.2 210.84 ;
     RECT  243.26 210.665 264.99 210.84 ;
     RECT  244.97 210.84 264.99 211.26 ;
     RECT  247.25 211.26 264.99 212.1 ;
     RECT  127.55 210.84 236.49 212.24 ;
     RECT  248.01 212.1 264.99 212.24 ;
     RECT  248.2 212.24 264.99 212.345 ;
     RECT  128.5 212.24 236.49 212.38 ;
     RECT  128.69 212.38 236.49 212.485 ;
     RECT  248.58 212.345 264.99 212.52 ;
     RECT  128.69 212.485 146.05 213.64 ;
     RECT  248.58 212.52 264.8 213.64 ;
     RECT  130.02 213.64 146.05 213.78 ;
     RECT  248.58 213.64 263.09 213.78 ;
     RECT  149.97 212.485 236.49 214.305 ;
     RECT  131.92 213.78 146.05 214.585 ;
     RECT  131.92 214.585 145.86 214.62 ;
     RECT  131.92 214.62 145.48 214.865 ;
     RECT  248.58 213.78 257.58 214.865 ;
     RECT  132.11 214.865 145.48 214.9 ;
     RECT  248.58 214.865 257.01 214.9 ;
     RECT  134.01 214.9 145.48 215.145 ;
     RECT  134.58 215.145 145.29 215.18 ;
     RECT  136.29 215.18 143.96 215.88 ;
     RECT  248.58 214.9 256.63 216.3 ;
     RECT  136.29 215.88 138.64 216.44 ;
     RECT  142.56 215.88 143.96 216.44 ;
     RECT  248.39 216.3 256.63 216.44 ;
     RECT  250.67 216.44 256.63 216.58 ;
     RECT  137.43 216.44 137.88 216.685 ;
     RECT  143.32 216.44 143.58 216.685 ;
     RECT  143.32 216.685 143.39 216.72 ;
     RECT  253.52 216.58 254.92 217.28 ;
     RECT  149.97 214.305 236.3 217.56 ;
     RECT  253.9 217.28 254.92 217.665 ;
     RECT  253.9 217.665 254.35 217.7 ;
     RECT  149.78 217.56 236.3 219.38 ;
     RECT  150.54 219.38 236.3 219.52 ;
     RECT  151.11 219.52 236.3 220.5 ;
     RECT  240.41 216.3 240.48 222.88 ;
     RECT  151.49 220.5 236.3 223.16 ;
     RECT  151.49 223.16 240.1 223.3 ;
     RECT  151.87 223.3 236.49 223.86 ;
     RECT  152.06 223.86 236.49 224.245 ;
     RECT  152.44 224.245 236.49 224.84 ;
     RECT  388.99 209.72 389.82 226.24 ;
     RECT  153.2 224.84 236.49 226.38 ;
     RECT  153.2 226.38 226.23 227.64 ;
     RECT  389.18 226.24 389.82 228.76 ;
     RECT  230.15 226.38 236.49 228.9 ;
     RECT  153.2 227.64 181.39 230.72 ;
     RECT  158.71 230.72 181.39 230.86 ;
     RECT  158.71 230.86 180.06 231.7 ;
     RECT  160.42 231.7 174.74 231.98 ;
     RECT  160.42 231.98 173.41 232.12 ;
     RECT  185.5 227.64 226.23 232.82 ;
     RECT  230.15 228.9 233.45 232.82 ;
     RECT  185.5 232.82 233.45 233.24 ;
     RECT  161.18 232.12 173.41 233.38 ;
     RECT  161.37 233.38 173.41 233.485 ;
     RECT  170.3 233.485 173.41 233.52 ;
     RECT  161.37 233.485 165.05 233.735 ;
     RECT  171.06 233.52 173.41 233.735 ;
     RECT  185.69 233.24 233.45 233.735 ;
     RECT  162.32 233.735 164.67 234.08 ;
     RECT  171.25 233.735 173.41 234.08 ;
     RECT  171.25 234.08 172.27 234.465 ;
     RECT  162.32 234.08 164.48 234.5 ;
     RECT  171.82 234.465 172.27 234.5 ;
     RECT  185.69 233.735 228.89 234.5 ;
     RECT  185.69 234.5 228.7 234.92 ;
     RECT  185.69 234.92 225.28 235.62 ;
     RECT  185.69 235.62 223.95 236.005 ;
     RECT  185.69 236.005 223.76 236.04 ;
     RECT  185.88 236.04 222.05 236.32 ;
     RECT  185.88 236.32 220.53 236.46 ;
     RECT  187.21 236.46 220.53 237.86 ;
     RECT  187.59 237.86 220.53 238.84 ;
     RECT  187.59 238.84 219.77 238.945 ;
     RECT  187.78 238.945 219.77 238.98 ;
     RECT  188.16 238.98 219.77 239.82 ;
     RECT  389.75 228.76 389.82 239.96 ;
     RECT  188.16 239.82 219.2 242.9 ;
     RECT  188.35 242.9 219.01 243.04 ;
     RECT  188.54 243.04 218.82 243.18 ;
     RECT  188.54 243.18 217.87 243.985 ;
     RECT  188.54 243.985 217.68 244.02 ;
     RECT  188.54 244.02 217.11 244.16 ;
     RECT  188.54 244.16 216.92 244.44 ;
     RECT  188.54 244.44 215.97 247.52 ;
     RECT  188.54 247.52 208.37 248.5 ;
     RECT  213.81 247.52 215.97 248.5 ;
     RECT  188.54 248.5 207.8 248.78 ;
     RECT  188.16 248.78 207.23 248.92 ;
     RECT  214.95 248.5 215.97 248.92 ;
     RECT  215.33 248.92 215.97 251.02 ;
     RECT  215.33 251.02 217.68 251.16 ;
     RECT  215.33 251.16 216.16 251.3 ;
     RECT  207.16 248.92 207.23 253.615 ;
     RECT  207.16 253.615 207.42 253.685 ;
     RECT  188.16 248.92 203.05 273.635 ;
     RECT  233.38 233.735 233.45 389.2 ;
     RECT  207.35 253.685 207.42 389.48 ;
     RECT  179.99 231.7 180.06 389.62 ;
     RECT  188.16 273.635 202.86 389.62 ;
     RECT  188.16 389.62 202.1 389.76 ;
     RECT  153.2 230.72 153.27 389.9 ;
     RECT  188.16 389.76 201.91 389.965 ;
    LAYER metal3 ;
     RECT  0.025 188.895 0.035 200.585 ;
     RECT  0.035 188.895 0.405 201.705 ;
     RECT  0.405 188.895 119.915 202.265 ;
     RECT  119.915 188.895 120.295 203.385 ;
     RECT  120.295 188.895 120.675 205.065 ;
     RECT  120.675 188.895 120.74 205.205 ;
     RECT  120.74 188.895 121.815 205.485 ;
     RECT  121.815 188.895 122.765 206.045 ;
     RECT  122.765 188.895 123.335 209.545 ;
     RECT  123.335 188.895 127.515 209.965 ;
     RECT  127.515 188.895 128.655 212.205 ;
     RECT  128.655 188.895 129.985 212.765 ;
     RECT  129.985 188.895 131.885 213.745 ;
     RECT  131.885 188.755 132.075 213.745 ;
     RECT  132.075 188.475 132.645 213.745 ;
     RECT  132.835 183.995 133.025 184.065 ;
     RECT  132.645 188.195 133.025 213.745 ;
     RECT  133.025 183.855 133.405 184.065 ;
     RECT  133.405 182.595 133.595 184.065 ;
     RECT  133.595 182.455 133.785 184.065 ;
     RECT  133.785 182.455 134.355 184.345 ;
     RECT  133.025 188.195 134.355 214.865 ;
     RECT  134.355 179.655 134.735 214.865 ;
     RECT  0.025 169.995 135.495 170.065 ;
     RECT  134.735 178.115 136.255 214.865 ;
     RECT  135.495 169.995 136.635 171.605 ;
     RECT  136.635 169.995 137.015 172.865 ;
     RECT  137.015 168.875 137.395 172.865 ;
     RECT  137.395 153.895 137.585 153.965 ;
     RECT  137.585 152.215 137.775 153.965 ;
     RECT  137.395 157.815 137.775 157.885 ;
     RECT  137.395 168.875 137.775 174.405 ;
     RECT  136.255 178.115 137.775 216.405 ;
     RECT  137.775 152.215 137.82 157.885 ;
     RECT  137.775 168.875 138.485 216.405 ;
     RECT  138.485 205.835 138.675 216.405 ;
     RECT  137.82 151.935 139.295 157.885 ;
     RECT  139.295 150.395 139.485 160.125 ;
     RECT  139.485 150.395 139.675 160.265 ;
     RECT  139.675 150.255 140.055 160.265 ;
     RECT  140.055 150.255 140.245 160.545 ;
     RECT  140.245 148.015 140.625 160.545 ;
     RECT  140.435 164.115 140.625 164.185 ;
     RECT  140.625 164.115 140.815 164.325 ;
     RECT  140.625 148.015 141.005 160.685 ;
     RECT  140.815 164.115 141.005 164.465 ;
     RECT  138.485 168.875 141.005 202.265 ;
     RECT  138.675 205.835 141.385 215.845 ;
     RECT  141.005 147.315 142.145 202.265 ;
     RECT  141.385 205.135 142.145 215.845 ;
     RECT  140.625 143.815 142.525 143.885 ;
     RECT  142.145 147.315 142.525 215.845 ;
     RECT  142.525 143.675 142.715 143.885 ;
     RECT  142.525 147.315 143.425 216.405 ;
     RECT  142.715 143.255 143.665 143.885 ;
     RECT  143.425 147.315 143.805 214.865 ;
     RECT  143.805 147.315 143.995 214.725 ;
     RECT  143.665 143.255 144.235 144.445 ;
     RECT  143.995 147.315 144.235 214.585 ;
     RECT  144.235 143.255 144.805 214.585 ;
     RECT  144.805 142.975 145.135 214.585 ;
     RECT  145.135 142.975 145.515 213.605 ;
     RECT  145.515 142.975 146.895 212.905 ;
     RECT  146.895 142.555 147.085 212.905 ;
     RECT  147.085 141.995 148.985 212.905 ;
     RECT  148.985 141.715 149.935 212.905 ;
     RECT  149.745 217.595 149.935 217.665 ;
     RECT  149.935 141.715 150.315 214.725 ;
     RECT  149.935 217.595 150.315 218.925 ;
     RECT  150.315 141.715 150.505 218.925 ;
     RECT  150.505 141.715 150.835 219.485 ;
     RECT  150.835 154.455 151.075 219.485 ;
     RECT  151.075 154.455 151.455 220.465 ;
     RECT  150.835 141.715 151.645 151.585 ;
     RECT  151.455 154.455 151.835 222.845 ;
     RECT  151.835 154.455 152.405 223.825 ;
     RECT  151.645 140.455 153.355 151.585 ;
     RECT  153.355 140.035 154.115 151.585 ;
     RECT  152.405 154.455 154.115 224.805 ;
     RECT  154.115 140.035 154.305 224.805 ;
     RECT  154.305 140.035 154.685 227.465 ;
     RECT  154.685 140.035 155.445 228.865 ;
     RECT  155.445 140.035 155.825 229.425 ;
     RECT  155.825 140.035 156.205 230.265 ;
     RECT  156.205 140.035 159.245 230.405 ;
     RECT  159.245 140.035 160.145 230.965 ;
     RECT  160.145 140.595 160.385 230.965 ;
     RECT  160.385 140.595 161.145 232.085 ;
     RECT  161.145 140.595 163.045 233.205 ;
     RECT  163.045 140.595 163.565 233.345 ;
     RECT  163.565 141.015 164.755 233.345 ;
     RECT  164.755 141.015 167.175 233.485 ;
     RECT  167.175 143.955 167.745 233.485 ;
     RECT  167.745 145.635 171.595 233.485 ;
     RECT  171.595 145.635 173.305 234.045 ;
     RECT  173.305 145.355 173.445 234.045 ;
     RECT  167.175 141.015 173.815 141.085 ;
     RECT  173.445 145.355 174.255 231.665 ;
     RECT  173.815 140.875 175.965 141.085 ;
     RECT  174.255 145.075 175.965 231.665 ;
     RECT  175.965 140.875 177.435 231.665 ;
     RECT  153.165 389.795 179.955 389.865 ;
     RECT  177.435 140.875 180.715 231.525 ;
     RECT  180.715 139.895 181.425 231.525 ;
     RECT  181.425 139.895 182.945 227.605 ;
     RECT  182.945 139.895 184.655 225.505 ;
     RECT  181.425 230.755 185.465 231.525 ;
     RECT  185.465 228.935 185.655 233.065 ;
     RECT  185.655 228.935 185.845 235.865 ;
     RECT  185.845 228.935 186.225 236.425 ;
     RECT  184.655 172.795 186.415 225.505 ;
     RECT  186.415 172.795 186.605 225.785 ;
     RECT  186.225 228.795 186.605 236.425 ;
     RECT  184.655 139.895 186.795 169.645 ;
     RECT  186.605 172.795 187.175 236.425 ;
     RECT  187.175 172.795 187.905 237.825 ;
     RECT  186.795 139.475 187.935 169.645 ;
     RECT  187.905 172.795 187.935 239.365 ;
     RECT  188.125 242.795 188.315 242.865 ;
     RECT  187.935 139.475 188.505 239.365 ;
     RECT  188.315 242.795 188.695 243.005 ;
     RECT  188.125 248.815 188.695 248.885 ;
     RECT  188.695 242.795 189.075 243.145 ;
     RECT  189.265 0.735 189.455 0.805 ;
     RECT  179.955 389.515 189.645 389.865 ;
     RECT  189.075 242.515 190.025 245.665 ;
     RECT  188.695 248.815 190.025 251.265 ;
     RECT  190.025 242.515 190.165 251.265 ;
     RECT  189.455 0.315 190.215 0.805 ;
     RECT  188.505 139.195 190.215 239.365 ;
     RECT  190.215 0.035 190.785 0.805 ;
     RECT  190.215 139.195 190.785 239.645 ;
     RECT  190.165 242.515 190.785 248.885 ;
     RECT  190.785 0.035 191.545 1.085 ;
     RECT  189.645 388.675 192.065 389.865 ;
     RECT  192.305 119.735 192.825 119.805 ;
     RECT  192.065 388.815 193.015 389.865 ;
     RECT  190.785 139.195 193.825 248.885 ;
     RECT  193.825 138.915 194.205 248.885 ;
     RECT  191.545 0.035 194.395 1.225 ;
     RECT  194.395 0.035 194.535 1.505 ;
     RECT  194.205 138.915 194.535 251.125 ;
     RECT  194.535 0.175 195.295 1.505 ;
     RECT  195.295 0.315 195.535 1.505 ;
     RECT  194.535 139.755 195.535 251.125 ;
     RECT  195.535 139.755 195.865 251.265 ;
     RECT  195.865 139.755 196.165 169.505 ;
     RECT  195.865 172.375 196.245 251.265 ;
     RECT  196.165 141.015 196.435 169.505 ;
     RECT  196.245 250.215 196.485 251.265 ;
     RECT  193.015 388.955 196.865 389.865 ;
     RECT  196.245 172.375 197.005 247.205 ;
     RECT  196.485 250.215 197.195 251.685 ;
     RECT  196.435 141.155 197.765 169.505 ;
     RECT  196.865 125.475 197.955 125.545 ;
     RECT  195.535 0.315 198.385 1.785 ;
     RECT  198.385 0.175 198.58 1.785 ;
     RECT  196.865 388.675 198.905 389.865 ;
     RECT  197.765 141.995 198.955 169.505 ;
     RECT  197.005 172.375 198.955 246.365 ;
     RECT  197.195 251.055 199.095 251.685 ;
     RECT  198.58 0.035 200.285 1.785 ;
     RECT  198.955 141.995 200.285 246.365 ;
     RECT  200.285 141.995 200.475 246.925 ;
     RECT  200.475 141.995 200.995 247.205 ;
     RECT  200.285 0.035 201.185 1.925 ;
     RECT  198.905 389.095 201.205 389.865 ;
     RECT  200.995 144.935 201.375 247.205 ;
     RECT  200.995 141.995 201.565 142.065 ;
     RECT  201.375 145.215 201.565 247.205 ;
     RECT  201.565 145.355 201.755 247.205 ;
     RECT  201.755 145.915 201.805 247.205 ;
     RECT  199.095 251.055 201.805 251.265 ;
     RECT  201.205 389.095 202.135 389.725 ;
     RECT  201.805 145.915 202.325 251.265 ;
     RECT  202.325 145.915 202.515 149.625 ;
     RECT  202.515 145.915 202.705 149.485 ;
     RECT  202.325 153.195 202.705 251.265 ;
     RECT  202.705 145.915 202.895 149.345 ;
     RECT  202.135 389.095 202.895 389.585 ;
     RECT  202.705 165.375 203.465 251.265 ;
     RECT  202.895 145.915 204.985 149.065 ;
     RECT  202.705 153.195 204.985 162.225 ;
     RECT  203.465 165.375 205.235 222.285 ;
     RECT  204.985 153.755 205.745 162.225 ;
     RECT  204.985 145.915 205.935 145.985 ;
     RECT  205.745 154.455 206.315 155.085 ;
     RECT  206.315 154.875 206.695 155.085 ;
     RECT  202.895 389.095 207.455 389.445 ;
     RECT  205.745 158.795 207.505 162.225 ;
     RECT  207.505 158.795 207.695 162.505 ;
     RECT  205.235 165.375 207.695 222.145 ;
     RECT  207.695 158.795 208.835 222.145 ;
     RECT  203.465 225.155 208.835 251.265 ;
     RECT  201.185 0.035 208.975 1.785 ;
     RECT  208.975 0.035 210.115 1.365 ;
     RECT  208.835 158.795 210.735 251.265 ;
     RECT  210.735 158.515 213.915 251.265 ;
     RECT  213.915 158.515 214.485 236.845 ;
     RECT  214.485 158.515 214.675 236.425 ;
     RECT  213.915 239.715 215.055 251.265 ;
     RECT  215.055 239.715 215.815 248.045 ;
     RECT  215.815 247.975 216.005 248.045 ;
     RECT  215.055 251.055 216.195 251.265 ;
     RECT  215.815 239.715 216.955 244.405 ;
     RECT  216.955 239.715 217.145 244.125 ;
     RECT  214.675 158.795 217.385 236.425 ;
     RECT  216.195 251.055 217.715 251.125 ;
     RECT  217.385 158.795 218.285 236.705 ;
     RECT  217.145 239.715 218.855 243.145 ;
     RECT  218.855 239.715 219.045 243.005 ;
     RECT  218.285 159.215 219.095 236.705 ;
     RECT  219.045 239.715 219.095 242.865 ;
     RECT  219.095 159.215 219.235 242.865 ;
     RECT  219.235 159.215 220.375 240.625 ;
     RECT  220.375 159.915 220.565 240.625 ;
     RECT  220.565 188.335 222.085 236.285 ;
     RECT  220.565 159.915 222.655 184.345 ;
     RECT  222.085 188.335 222.845 236.005 ;
     RECT  222.845 232.855 223.035 236.005 ;
     RECT  222.655 160.195 223.605 184.345 ;
     RECT  223.605 160.475 223.795 184.345 ;
     RECT  223.795 160.475 224.745 180.845 ;
     RECT  224.745 160.475 224.935 161.525 ;
     RECT  224.935 160.475 224.97 160.685 ;
     RECT  223.795 183.995 224.985 184.345 ;
     RECT  222.845 188.335 224.985 229.985 ;
     RECT  224.97 160.615 225.125 160.685 ;
     RECT  224.985 183.995 225.125 229.985 ;
     RECT  225.125 183.995 225.885 228.865 ;
     RECT  224.745 164.395 226.265 180.845 ;
     RECT  225.885 188.335 226.455 228.865 ;
     RECT  226.265 180.775 227.025 180.845 ;
     RECT  226.455 188.475 227.805 228.865 ;
     RECT  226.265 165.795 228.165 176.925 ;
     RECT  227.805 222.215 228.355 228.865 ;
     RECT  223.035 232.855 228.545 234.885 ;
     RECT  228.165 176.855 228.735 176.925 ;
     RECT  228.545 232.995 228.735 234.885 ;
     RECT  227.265 182.735 228.925 183.085 ;
     RECT  228.165 165.795 229.115 173.005 ;
     RECT  228.355 222.635 229.495 228.865 ;
     RECT  228.925 182.735 229.685 182.805 ;
     RECT  229.495 222.915 230.825 228.865 ;
     RECT  230.825 225.155 231.015 228.865 ;
     RECT  227.805 188.475 231.585 219.205 ;
     RECT  231.585 189.455 231.775 219.205 ;
     RECT  210.115 0.035 233.105 0.525 ;
     RECT  231.775 189.735 233.105 218.085 ;
     RECT  207.455 389.095 233.485 389.165 ;
     RECT  220.565 240.555 233.665 240.625 ;
     RECT  231.015 225.855 233.735 228.865 ;
     RECT  233.665 239.855 233.735 240.625 ;
     RECT  233.735 226.135 236.525 228.865 ;
     RECT  233.105 189.735 236.575 216.545 ;
     RECT  236.575 189.595 239.425 216.545 ;
     RECT  236.195 223.195 240.135 223.265 ;
     RECT  239.425 188.335 242.415 216.545 ;
     RECT  242.415 188.755 243.175 216.545 ;
     RECT  243.175 189.595 245.725 216.545 ;
     RECT  233.105 0.035 246.025 0.245 ;
     RECT  246.025 0.035 247.925 0.105 ;
     RECT  245.725 189.735 253.485 216.545 ;
     RECT  253.485 189.735 254.195 217.245 ;
     RECT  254.195 189.735 256.665 216.545 ;
     RECT  256.665 189.735 263.125 213.745 ;
     RECT  263.125 189.735 264.835 213.605 ;
     RECT  264.835 189.735 265.025 212.345 ;
     RECT  265.025 189.735 265.785 206.745 ;
     RECT  265.785 189.735 267.305 204.225 ;
     RECT  265.025 209.615 334.375 210.385 ;
     RECT  267.305 189.735 373.385 202.965 ;
     RECT  373.385 190.015 387.195 202.965 ;
     RECT  387.195 190.015 388.005 201.565 ;
     RECT  229.115 172.935 388.145 173.005 ;
     RECT  229.115 165.795 388.525 169.505 ;
     RECT  388.525 165.795 388.715 167.685 ;
     RECT  388.005 188.615 388.715 201.565 ;
     RECT  334.375 209.615 388.905 209.685 ;
     RECT  388.715 165.795 389.095 166.145 ;
     RECT  236.525 226.135 389.095 228.725 ;
     RECT  389.095 226.695 389.285 228.725 ;
     RECT  206.695 155.015 389.475 155.085 ;
     RECT  389.285 226.695 389.475 226.765 ;
     RECT  389.095 165.795 389.665 165.865 ;
     RECT  388.715 188.615 389.665 201.425 ;
     RECT  204.985 148.995 389.855 149.065 ;
     RECT  233.735 239.855 389.855 239.925 ;
     RECT  389.665 188.755 389.965 201.425 ;
    LAYER metal4 ;
     RECT  192.665 0.14 192.805 139.72 ;
     RECT  190.705 139.72 196.165 142.24 ;
     RECT  190.425 142.24 196.165 149.1 ;
     RECT  190.425 149.1 200.085 152.04 ;
     RECT  190.425 152.04 201.205 152.88 ;
     RECT  190.705 152.88 201.205 153.58 ;
     RECT  190.985 153.58 201.205 156.52 ;
     RECT  190.985 156.52 194.765 160.58 ;
     RECT  201.065 156.52 201.205 165.62 ;
     RECT  178.665 164.36 178.805 165.76 ;
     RECT  201.065 165.62 205.685 165.9 ;
     RECT  178.665 165.76 179.645 167.72 ;
     RECT  201.065 165.9 207.365 170.66 ;
     RECT  188.465 160.58 194.765 171.92 ;
     RECT  201.065 170.66 208.765 171.92 ;
     RECT  177.825 167.72 179.645 172.34 ;
     RECT  188.465 171.92 208.765 173.32 ;
     RECT  188.465 173.32 207.365 173.88 ;
     RECT  179.505 172.34 179.645 176.96 ;
     RECT  185.385 173.88 207.365 177.24 ;
     RECT  185.385 177.24 207.085 178.64 ;
     RECT  139.745 179.62 139.885 179.76 ;
     RECT  182.585 178.64 207.085 179.76 ;
     RECT  182.585 179.76 182.725 182.7 ;
     RECT  165.785 183.68 165.925 184.94 ;
     RECT  189.305 179.76 207.085 185.92 ;
     RECT  189.305 185.92 206.525 186.76 ;
     RECT  181.465 182.7 182.725 187.88 ;
     RECT  188.745 186.76 206.525 189.42 ;
     RECT  179.225 187.88 182.725 190.82 ;
     RECT  245.585 189.56 245.725 190.82 ;
     RECT  245.585 190.82 249.085 191.24 ;
     RECT  245.305 191.24 249.085 192.22 ;
     RECT  228.505 182.98 228.645 192.36 ;
     RECT  245.305 192.22 254.125 192.36 ;
     RECT  243.065 192.36 254.125 192.5 ;
     RECT  178.665 190.82 182.725 192.64 ;
     RECT  188.745 189.42 205.965 192.64 ;
     RECT  139.745 179.76 142.685 192.92 ;
     RECT  165.785 184.94 170.405 193.62 ;
     RECT  178.665 192.64 205.965 193.62 ;
     RECT  237.185 192.36 237.325 193.76 ;
     RECT  140.025 192.92 142.685 194.32 ;
     RECT  140.025 194.32 144.365 194.46 ;
     RECT  244.185 192.5 254.125 194.46 ;
     RECT  140.025 194.46 142.685 194.6 ;
     RECT  228.505 192.36 228.925 194.74 ;
     RECT  237.185 193.76 237.605 195.44 ;
     RECT  244.185 194.46 249.085 195.72 ;
     RECT  237.185 195.44 237.325 196 ;
     RECT  244.185 195.72 246.285 196.84 ;
     RECT  244.185 196.84 244.325 197.12 ;
     RECT  165.785 193.62 205.965 198.38 ;
     RECT  129.105 197.54 129.245 198.52 ;
     RECT  128.545 198.52 129.245 198.66 ;
     RECT  140.025 194.6 140.165 198.94 ;
     RECT  224.305 194.74 228.925 199.22 ;
     RECT  165.785 198.38 202.045 199.36 ;
     RECT  255.385 194.74 255.525 199.5 ;
     RECT  128.545 198.66 128.965 199.64 ;
     RECT  224.305 199.22 230.045 199.64 ;
     RECT  0.025 193.2 0.165 199.78 ;
     RECT  159.905 199.64 160.045 200.06 ;
     RECT  165.785 199.36 175.725 200.06 ;
     RECT  159.905 200.06 175.725 200.34 ;
     RECT  159.905 200.34 175.445 200.62 ;
     RECT  134.985 200.76 135.125 200.9 ;
     RECT  389.785 200.2 389.925 200.9 ;
     RECT  159.905 200.62 175.165 201.6 ;
     RECT  211.705 200.48 211.845 201.74 ;
     RECT  222.345 199.64 230.045 201.88 ;
     RECT  211.705 201.74 213.245 202.02 ;
     RECT  220.665 201.88 230.045 202.02 ;
     RECT  159.905 201.6 170.965 202.3 ;
     RECT  182.585 199.36 202.045 202.3 ;
     RECT  159.625 202.3 170.965 202.44 ;
     RECT  159.625 202.44 169.285 202.58 ;
     RECT  211.705 202.02 230.045 205.38 ;
     RECT  151.225 206.5 151.365 207.34 ;
     RECT  127.705 199.64 128.965 208.18 ;
     RECT  183.425 202.3 202.045 208.6 ;
     RECT  211.705 205.38 227.805 208.6 ;
     RECT  150.665 207.34 151.365 208.88 ;
     RECT  151.225 208.88 151.365 209.02 ;
     RECT  127.705 208.18 127.845 209.16 ;
     RECT  254.545 209.16 254.685 209.3 ;
     RECT  159.625 202.58 165.925 210.98 ;
     RECT  164.385 210.98 165.925 212.94 ;
     RECT  250.625 211.96 250.765 213.92 ;
     RECT  183.425 208.6 227.805 214.2 ;
     RECT  164.385 212.94 164.525 214.76 ;
     RECT  183.985 214.2 227.805 216.44 ;
     RECT  184.825 216.44 227.805 216.72 ;
     RECT  187.905 216.72 227.805 219.24 ;
     RECT  187.905 219.24 214.925 219.38 ;
     RECT  157.385 217.56 157.525 219.52 ;
     RECT  224.025 219.24 227.805 219.52 ;
     RECT  163.825 219.94 164.245 220.22 ;
     RECT  187.905 219.38 206.245 220.78 ;
     RECT  187.905 220.78 205.685 220.92 ;
     RECT  213.105 219.38 214.925 220.92 ;
     RECT  163.545 220.22 164.245 222.04 ;
     RECT  214.785 220.92 214.925 222.32 ;
     RECT  164.105 222.04 164.245 223.3 ;
     RECT  224.025 219.52 224.445 223.3 ;
     RECT  224.025 223.3 224.165 228.48 ;
     RECT  187.905 220.92 201.205 234.64 ;
     RECT  187.905 234.64 201.485 239.4 ;
     RECT  192.665 239.4 201.485 243.18 ;
     RECT  192.665 243.18 201.205 245.7 ;
     RECT  193.785 245.7 201.205 245.84 ;
     RECT  194.345 245.84 201.205 250.46 ;
     RECT  199.665 250.46 201.205 389.9 ;
    LAYER metal5 ;
     RECT  0.025 199.64 134.985 199.78 ;
     RECT  134.985 199.64 179.505 200.9 ;
     RECT  179.505 198.8 182.585 200.9 ;
     RECT  182.585 198.8 184.965 202.3 ;
     RECT  184.965 198.8 185.525 200.9 ;
     RECT  184.825 208.6 196.585 208.74 ;
     RECT  196.585 208.6 213.245 209.3 ;
     RECT  185.525 199.64 222.485 200.9 ;
     RECT  243.065 192.36 250.485 192.5 ;
     RECT  213.245 209.16 254.685 209.3 ;
     RECT  222.485 200.76 389.925 200.9 ;
  END
END dot_product
END LIBRARY
